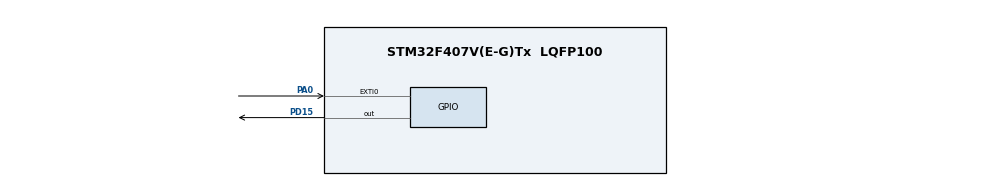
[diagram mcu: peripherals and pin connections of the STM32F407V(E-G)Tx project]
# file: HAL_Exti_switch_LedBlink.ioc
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Mcu.Family=STM32F4
Mcu.Name=STM32F407V(E-G)Tx
Mcu.Package=LQFP100
NVIC.EXTI0_IRQn=true\:0\:0\:false\:false\:true\:true\:true\:true
NVIC.PriorityGroup=NVIC_PRIORITYGROUP_0
PA0-WKUP.Signal=GPXTI0
PD15.Signal=GPIO_Output
ProjectManager.HeapSize=0x200
ProjectManager.StackSize=0x400
ProjectManager.TargetToolchain=STM32CubeIDE
RCC.48MHZClocksFreq_Value=48000000
RCC.AHBFreq_Value=168000000
RCC.APB1CLKDivider=RCC_HCLK_DIV4
RCC.APB1Freq_Value=42000000
RCC.APB1TimFreq_Value=84000000
RCC.APB2CLKDivider=RCC_HCLK_DIV2
RCC.APB2Freq_Value=84000000
RCC.APB2TimFreq_Value=168000000
RCC.CortexFreq_Value=168000000
RCC.HCLKFreq_Value=168000000
RCC.HSE_VALUE=8000000
RCC.HSI_VALUE=16000000
RCC.PLLM=8
RCC.PLLN=336
RCC.PLLQ=7
RCC.PLLSourceVirtual=RCC_PLLSOURCE_HSE
RCC.SYSCLKFreq_VALUE=168000000
RCC.SYSCLKSource=RCC_SYSCLKSOURCE_PLLCLK
RCC.VCOOutputFreq_Value=336000000
board=STM32F407G-DISC1

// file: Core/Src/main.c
/* USER CODE BEGIN Header */
/**
  ******************************************************************************
  * @file           : main.c
  * @brief          : Main program body
  ******************************************************************************
  * @attention
  *
  * Copyright (c) 2026 STMicroelectronics.
  * All rights reserved.
  *
  * This software is licensed under terms that can be found in the LICENSE file
  * in the root directory of this software component.
  * If no LICENSE file comes with this software, it is provided AS-IS.
  *
  ******************************************************************************
  */
/* USER CODE END Header */
#include "main.h"

/* USER CODE BEGIN PV */
volatile uint32_t switch_flag = 0;
/* USER CODE END PV */

void SystemClock_Config(void);
static void MX_GPIO_Init(void);

int main(void)
{

  /* MCU Configuration--------------------------------------------------------*/

  /* Reset of all peripherals, Initializes the Flash interface and the Systick. */
  HAL_Init();

  /* Configure the system clock */
  SystemClock_Config();

  /* Initialize all configured peripherals */
  MX_GPIO_Init();

  /* Infinite loop */
  /* USER CODE BEGIN WHILE */
  while (1)
  {
	  // wait for switch press interrupt (callback)
	  while(switch_flag == 0)
		  ;
	  // blink the led
	  HAL_GPIO_WritePin(GPIOD, GPIO_PIN_14, GPIO_PIN_SET);
	  HAL_Delay(1000);
	  HAL_GPIO_WritePin(GPIOD, GPIO_PIN_14, GPIO_PIN_RESET);
	  // clear the switch flag
	  switch_flag = 0;
    /* USER CODE END WHILE */

  }
}

void SystemClock_Config(void)
{
  RCC_OscInitTypeDef RCC_OscInitStruct = {0};
  RCC_ClkInitTypeDef RCC_ClkInitStruct = {0};

  /** Configure the main internal regulator output voltage
  */
  __HAL_RCC_PWR_CLK_ENABLE();
  __HAL_PWR_VOLTAGESCALING_CONFIG(PWR_REGULATOR_VOLTAGE_SCALE1);

  /** Initializes the RCC Oscillators according to the specified parameters
  * in the RCC_OscInitTypeDef structure.
  */
  RCC_OscInitStruct.OscillatorType = RCC_OSCILLATORTYPE_HSI;
  RCC_OscInitStruct.HSIState = RCC_HSI_ON;
  RCC_OscInitStruct.HSICalibrationValue = RCC_HSICALIBRATION_DEFAULT;
  RCC_OscInitStruct.PLL.PLLState = RCC_PLL_ON;
  RCC_OscInitStruct.PLL.PLLSource = RCC_PLLSOURCE_HSI;
  RCC_OscInitStruct.PLL.PLLM = 8;
  RCC_OscInitStruct.PLL.PLLN = 50;
  RCC_OscInitStruct.PLL.PLLP = RCC_PLLP_DIV4;
  RCC_OscInitStruct.PLL.PLLQ = 7;
  if (HAL_RCC_OscConfig(&RCC_OscInitStruct) != HAL_OK)
  {
    Error_Handler();
  }

  /** Initializes the CPU, AHB and APB buses clocks
  */
  RCC_ClkInitStruct.ClockType = RCC_CLOCKTYPE_HCLK|RCC_CLOCKTYPE_SYSCLK
                              |RCC_CLOCKTYPE_PCLK1|RCC_CLOCKTYPE_PCLK2;
  RCC_ClkInitStruct.SYSCLKSource = RCC_SYSCLKSOURCE_PLLCLK;
  RCC_ClkInitStruct.AHBCLKDivider = RCC_SYSCLK_DIV1;
  RCC_ClkInitStruct.APB1CLKDivider = RCC_HCLK_DIV4;
  RCC_ClkInitStruct.APB2CLKDivider = RCC_HCLK_DIV2;

  if (HAL_RCC_ClockConfig(&RCC_ClkInitStruct, FLASH_LATENCY_0) != HAL_OK)
  {
    Error_Handler();
  }
}

static void MX_GPIO_Init(void)
{
  GPIO_InitTypeDef GPIO_InitStruct = {0};

  /* GPIO Ports Clock Enable */
  __HAL_RCC_GPIOA_CLK_ENABLE();
  __HAL_RCC_GPIOD_CLK_ENABLE();

  /*Configure GPIO pin Output Level */
  HAL_GPIO_WritePin(GPIOD, GPIO_PIN_14, GPIO_PIN_RESET);

  /*Configure GPIO pin : PA0 */
  GPIO_InitStruct.Pin = GPIO_PIN_0;
  GPIO_InitStruct.Mode = GPIO_MODE_IT_RISING;
  GPIO_InitStruct.Pull = GPIO_NOPULL;
  HAL_GPIO_Init(GPIOA, &GPIO_InitStruct);

  /*Configure GPIO pin : PD14 */
  GPIO_InitStruct.Pin = GPIO_PIN_14;
  GPIO_InitStruct.Mode = GPIO_MODE_OUTPUT_PP;
  GPIO_InitStruct.Pull = GPIO_NOPULL;
  GPIO_InitStruct.Speed = GPIO_SPEED_FREQ_LOW;
  HAL_GPIO_Init(GPIOD, &GPIO_InitStruct);

  /* EXTI interrupt init*/
  HAL_NVIC_SetPriority(EXTI0_IRQn, 0, 0);
  HAL_NVIC_EnableIRQ(EXTI0_IRQn);

}

/* USER CODE BEGIN 4 */
void HAL_GPIO_EXTI_Callback(uint16_t GPIO_Pin)
{
	// set the switch flag
	switch_flag = 1;
}
/* USER CODE END 4 */

void Error_Handler(void)
{
  __disable_irq();
  while (1)
  {
  }
}
